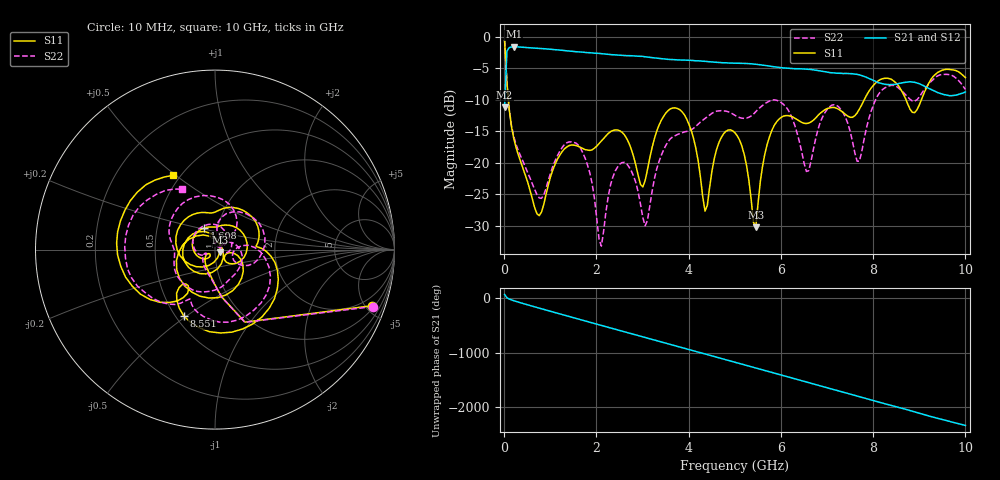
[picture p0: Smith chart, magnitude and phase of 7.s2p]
!Agilent Technologies,N5230C,MY49000813,A.09.42.22
!Agilent N5230C: A.09.42.22
!Date: Friday, August 21, 2026 19:38:39
!Correction: S11(Full 2 Port(1,2))
!S21(Full 2 Port(1,2))
!S12(Full 2 Port(1,2))
!S22(Full 2 Port(1,2))
!S2P File: Measurements: S11, S21, S12, S22:
# Hz S  dB  R 50
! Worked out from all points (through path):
!   201 points, 10 MHz to 10 GHz, reference 50 ohm
!   highest |S21| = -1.58 dB at 209.8 MHz (marker M1); lowest = -11.2 dB at 10 MHz (marker M2)
!   lowest |S11| = -30.2 dB at 5.455 GHz (marker M3), VSWR 1.06, Z = 52.8 - j1.51 ohm
!   |S11| at or under -10 dB: 92.09 MHz to 7.806 GHz (7.714 GHz wide, 195 % of centre); 8.712 GHz to 9.046 GHz (334 MHz wide, 3.76 % of centre)
!   |S22| runs from -33.2 to -0.6 dB; largest |S21 - S12| = 0.006
!   S11 on the Smith chart (normalised r, x): 10 MHz: 1.20, -5.52; 1.608 GHz: 0.86, +0.21; 8.551 GHz: 0.55, -0.49; 10 GHz: 0.46, +0.49
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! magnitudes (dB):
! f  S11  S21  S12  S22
! 10 MHz  -0.6  -11.2  -11.4  -0.6
! 59.95 MHz  -7.2  -2.3  -2.3  -7.2
! 209.8 MHz  -16.2  -1.6  -1.6  -15.9
! 759.2 MHz  -28.4  -1.8  -1.8  -25.6
! 1.608 GHz  -17.4  -2.4  -2.4  -17.2
! 1.708 GHz  -17.7  -2.4  -2.5  -18.5
! 2.108 GHz  -16.6  -2.7  -2.7  -33.2
! 2.507 GHz  -14.9  -2.9  -2.9  -20.2
! 3.007 GHz  -23.8  -3.1  -3.1  -28.7
! 3.357 GHz  -14.0  -3.4  -3.4  -19.8
! 3.956 GHz  -13.0  -3.7  -3.7  -15.0
! 4.356 GHz  -27.7  -3.9  -3.9  -13.0
! 4.655 GHz  -16.8  -4.1  -4.1  -11.8
! 5.005 GHz  -15.3  -4.2  -4.2  -12.5
! 5.455 GHz  -30.2  -4.4  -4.4  -11.9
! 5.854 GHz  -14.1  -4.8  -4.8  -10.0
! 6.703 GHz  -13.2  -5.2  -5.2  -17.9
! 7.203 GHz  -11.3  -5.8  -5.8  -10.9
! 7.702 GHz  -11.5  -6.0  -6.0  -19.7
! 8.352 GHz  -6.6  -7.6  -7.6  -7.8
! 8.551 GHz  -7.8  -7.4  -7.4  -8.1
! 10 GHz  -6.5  -8.8  -8.7  -8.4
